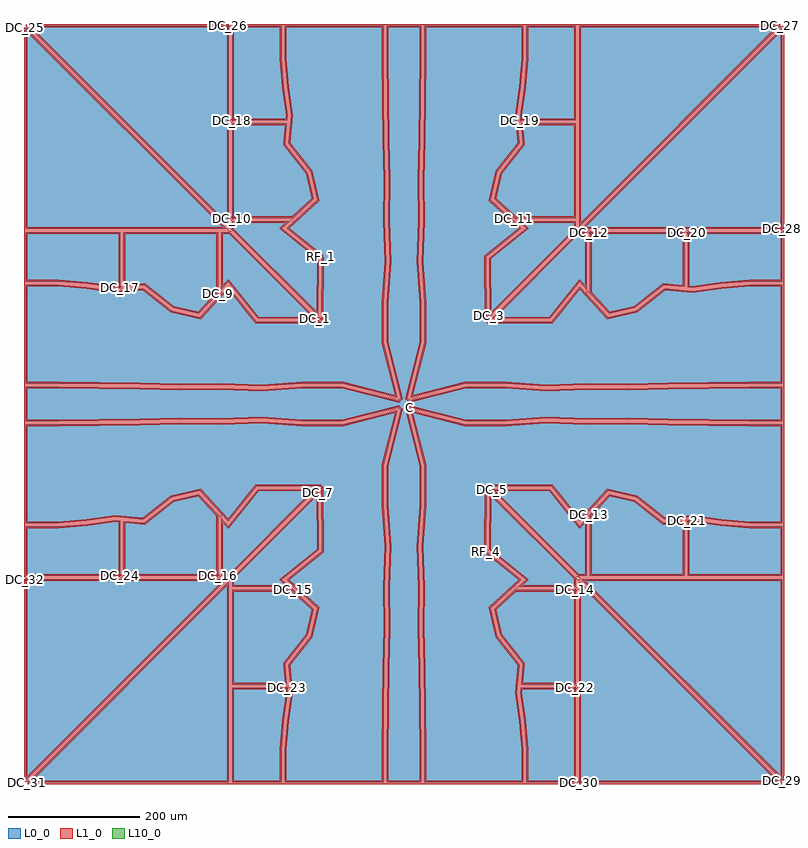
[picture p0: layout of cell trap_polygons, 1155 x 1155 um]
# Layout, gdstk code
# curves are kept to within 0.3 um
import gdstk
lib = gdstk.Library(unit=1e-6, precision=1e-09)
def P(c, l, *ps):  # polygons
    for p in ps: c.add(gdstk.Polygon(p, *l))
L0_0 = (0, 0)
L1_0 = (1, 0)
L10_0 = (10, 0)

trap_polygons = lib.new_cell('trap_polygons')
P(trap_polygons, L0_0, [(-575,-266.125),(-269.661,-266.125),(-575,-571.464),(-575,-266.125)],
  [(-571.464,-575),(-266.125,-269.661),(-266.125,-575),(-571.464,-575)],
  [(266.125,-575),(266.125,-269.661),(571.464,-575),(266.125,-575)],
  [(575,-571.464),(269.661,-266.125),(575,-266.125),(575,-571.464)],
  [(575,266.125),(269.661,266.125),(575,571.464),(575,266.125)],
  [(571.464,575),(266.125,269.661),(266.125,575),(571.464,575)],
  [(-266.125,575),(-266.125,269.661),(-571.464,575),(-266.125,575)],
  [(-575,571.464),(-269.661,266.125),(-575,266.125),(-575,571.464)],
  [(-431.321,-261.125),(-438.926,-261.125),(-481.19,-261.125),(-524.501,-261.125),(-575,-261.125),(-575,-186.125),(-524.501,-186.125),(-481.19,-182.401),(-438.926,-176.757),(-431.321,-177.452),(-431.321,-261.125)],
  [(-177.452,-431.321),(-176.757,-438.926),(-182.401,-481.19),(-186.125,-524.501),(-186.125,-575),(-261.125,-575),(-261.125,-524.501),(-261.125,-481.19),(-261.125,-438.926),(-261.125,-431.321),(-177.452,-431.321)],
  [(261.125,-431.321),(261.125,-438.926),(261.125,-481.19),(261.125,-524.501),(261.125,-575),(186.125,-575),(186.125,-524.501),(182.401,-481.19),(176.757,-438.926),(177.452,-431.321),(261.125,-431.321)],
  [(431.321,-177.452),(438.926,-176.757),(481.19,-182.401),(524.501,-186.125),(575,-186.125),(575,-261.125),(524.501,-261.125),(481.19,-261.125),(438.926,-261.125),(431.321,-261.125),(431.321,-177.452)],
  [(431.321,261.125),(438.926,261.125),(481.19,261.125),(524.501,261.125),(575,261.125),(575,186.125),(524.501,186.125),(481.19,182.401),(438.926,176.757),(431.321,177.452),(431.321,261.125)],
  [(177.452,431.321),(176.757,438.926),(182.401,481.19),(186.125,524.501),(186.125,575),(261.125,575),(261.125,524.501),(261.125,481.19),(261.125,438.926),(261.125,431.321),(177.452,431.321)],
  [(-261.125,431.321),(-261.125,438.926),(-261.125,481.19),(-261.125,524.501),(-261.125,575),(-186.125,575),(-186.125,524.501),(-182.401,481.19),(-176.757,438.926),(-177.452,431.321),(-261.125,431.321)],
  [(-431.321,177.452),(-438.926,176.757),(-481.19,182.401),(-524.501,186.125),(-575,186.125),(-575,261.125),(-524.501,261.125),(-481.19,261.125),(-438.926,261.125),(-431.321,261.125),(-431.321,177.452)],
  [(-282.643,-261.125),(-311.781,-261.125),(-350.84,-261.125),(-394.504,-261.125),(-426.321,-261.125),(-426.321,-177.909),(-394.504,-180.815),(-350.84,-146.071),(-311.781,-137.162),(-282.643,-168.581),(-282.643,-261.125)],
  [(-168.581,-282.643),(-137.162,-311.781),(-146.071,-350.84),(-180.815,-394.504),(-177.909,-426.321),(-261.125,-426.321),(-261.125,-394.504),(-261.125,-350.84),(-261.125,-311.781),(-261.125,-282.643),(-168.581,-282.643)],
  [(261.125,-282.643),(261.125,-311.781),(261.125,-350.84),(261.125,-394.504),(261.125,-426.321),(177.909,-426.321),(180.815,-394.504),(146.071,-350.84),(137.162,-311.781),(168.581,-282.643),(261.125,-282.643)],
  [(282.643,-168.581),(311.781,-137.162),(350.84,-146.071),(394.504,-180.815),(426.321,-177.909),(426.321,-261.125),(394.504,-261.125),(350.84,-261.125),(311.781,-261.125),(282.643,-261.125),(282.643,-168.581)],
  [(282.643,261.125),(311.781,261.125),(350.84,261.125),(394.504,261.125),(426.321,261.125),(426.321,177.909),(394.504,180.815),(350.84,146.071),(311.781,137.162),(282.643,168.581),(282.643,261.125)],
  [(168.581,282.643),(137.162,311.781),(146.071,350.84),(180.815,394.504),(177.909,426.321),(261.125,426.321),(261.125,394.504),(261.125,350.84),(261.125,311.781),(261.125,282.643),(168.581,282.643)],
  [(-261.125,282.643),(-261.125,311.781),(-261.125,350.84),(-261.125,394.504),(-261.125,426.321),(-177.909,426.321),(-180.815,394.504),(-146.071,350.84),(-137.162,311.781),(-168.581,282.643),(-261.125,282.643)],
  [(-282.643,168.581),(-311.781,137.162),(-350.84,146.071),(-394.504,180.815),(-426.321,177.909),(-426.321,261.125),(-394.504,261.125),(-350.84,261.125),(-311.781,261.125),(-282.643,261.125),(-282.643,168.581)],
  [(-264.661,-261.125),(-266.827,-261.125),(-277.643,-261.125),(-277.643,-173.972),(-266.827,-185.634),(-221.734,-129.646),(-133.964,-130.428),(-264.661,-261.125)],
  [(-130.428,-133.964),(-129.646,-221.734),(-185.634,-266.827),(-173.972,-277.643),(-261.125,-277.643),(-261.125,-266.827),(-261.125,-264.661),(-130.428,-133.964)],
  [(261.125,-264.661),(261.125,-266.827),(261.125,-277.643),(173.972,-277.643),(185.634,-266.827),(129.646,-221.734),(130.428,-133.964),(261.125,-264.661)],
  [(133.964,-130.428),(221.734,-129.646),(266.827,-185.634),(277.643,-173.972),(277.643,-261.125),(266.827,-261.125),(264.661,-261.125),(133.964,-130.428)],
  [(264.661,261.125),(266.827,261.125),(277.643,261.125),(277.643,173.972),(266.827,185.634),(221.734,129.646),(133.964,130.428),(264.661,261.125)],
  [(130.428,133.964),(129.646,221.734),(185.634,266.827),(173.972,277.643),(261.125,277.643),(261.125,266.827),(261.125,264.661),(130.428,133.964)],
  [(-261.125,264.661),(-261.125,266.827),(-261.125,277.643),(-173.972,277.643),(-185.634,266.827),(-129.646,221.734),(-130.428,133.964),(-261.125,264.661)],
  [(-133.964,130.428),(-221.734,129.646),(-266.827,185.634),(-277.643,173.972),(-277.643,261.125),(-266.827,261.125),(-264.661,261.125),(-133.964,130.428)],
  [(8.315,-5.556),(6.344,-7.73),(4.563,-8.89),(26.091,-93.487),(26.125,-154.417),(21.725,-216.238),(23.897,-278.128),(23.354,-339.827),(25.43,-463.123),(26.125,-525),(26.125,-575),(-26.125,-575),(-26.125,-525),(-25.43,-463.123),(-23.354,-339.827),(-23.897,-278.128),(-21.725,-216.238),(-26.125,-154.417),(-26.091,-93.487),(-4.563,-8.89),(-7.071,-7.071),(-8.89,-4.563),(-93.487,-26.091),(-154.417,-26.125),(-216.238,-21.725),(-278.128,-23.897),(-339.827,-23.354),(-463.123,-25.43),(-525,-26.125),(-575,-26.125),(-575,26.125),(-525,26.125),(-463.123,25.43),(-339.827,23.354),(-278.128,23.897),(-216.238,21.725),(-154.417,26.125),(-93.487,26.091),(-8.89,4.563),(-7.071,7.071),(-4.563,8.89),(-26.091,93.487),(-26.125,154.417),(-21.725,216.238),(-23.897,278.128),(-23.354,339.827),(-25.43,463.123),(-26.125,525),(-26.125,575),(26.125,575),(26.125,525),(25.43,463.123),(23.354,339.827),(23.897,278.128),(21.725,216.238),(26.125,154.417),(26.091,93.487),(4.563,8.89),(7.071,7.071),(8.89,4.563),(93.487,26.091),(154.417,26.125),(216.238,21.725),(278.128,23.897),(339.827,23.354),(463.123,25.43),(525,26.125),(575,26.125),(575,-26.125),(525,-26.125),(463.123,-25.43),(339.827,-23.354),(278.128,-23.897),(216.238,-21.725),(154.417,-26.125),(93.487,-26.091),(8.89,-4.563)],
  [(124.625,-224.109),(177.993,-267.094),(131.645,-310.078),(141.449,-353.062),(175.653,-396.047),(171.727,-439.031),(177.467,-482.016),(181.125,-525),(181.125,-575),(31.125,-575),(31.125,-525),(30.432,-463.266),(28.355,-339.797),(28.898,-278.062),(26.731,-216.328),(31.125,-154.594),(31.091,-92.859),(10.007,-10.007),(92.859,-31.091),(154.594,-31.125),(216.328,-26.731),(278.062,-28.898),(339.797,-28.355),(463.266,-30.432),(525,-31.125),(575,-31.125),(575,-181.125),(525,-181.125),(482.016,-177.467),(439.031,-171.727),(396.047,-175.653),(353.062,-141.449),(310.078,-131.645),(267.094,-177.993),(224.109,-124.625),(125.504,-125.504)],
  [(125.504,125.504),(224.109,124.625),(267.094,177.993),(310.078,131.645),(353.062,141.449),(396.047,175.653),(439.031,171.727),(482.016,177.467),(525,181.125),(575,181.125),(575,31.125),(525,31.125),(463.266,30.432),(339.797,28.355),(278.062,28.898),(216.328,26.731),(154.594,31.125),(92.859,31.091),(10.007,10.007),(31.091,92.859),(31.125,154.594),(26.731,216.328),(28.898,278.062),(28.355,339.797),(30.432,463.266),(31.125,525),(31.125,575),(181.125,575),(181.125,525),(177.467,482.016),(171.727,439.031),(175.653,396.047),(141.449,353.062),(131.645,310.078),(177.993,267.094),(124.625,224.109)],
  [(-125.504,-125.504),(-224.109,-124.625),(-267.094,-177.993),(-310.078,-131.645),(-353.062,-141.449),(-396.047,-175.653),(-439.031,-171.727),(-482.016,-177.467),(-525,-181.125),(-575,-181.125),(-575,-31.125),(-525,-31.125),(-463.266,-30.432),(-339.797,-28.355),(-278.062,-28.898),(-216.328,-26.731),(-154.594,-31.125),(-92.859,-31.091),(-10.007,-10.007),(-31.091,-92.859),(-31.125,-154.594),(-26.731,-216.328),(-28.898,-278.062),(-28.355,-339.797),(-30.432,-463.266),(-31.125,-525),(-31.125,-575),(-181.125,-575),(-181.125,-525),(-177.467,-482.016),(-171.727,-439.031),(-175.653,-396.047),(-141.449,-353.062),(-131.645,-310.078),(-177.993,-267.094),(-124.625,-224.109)],
  [(-124.625,224.109),(-177.993,267.094),(-131.645,310.078),(-141.449,353.062),(-175.653,396.047),(-171.727,439.031),(-177.467,482.016),(-181.125,525),(-181.125,575),(-31.125,575),(-31.125,525),(-30.432,463.266),(-28.355,339.797),(-28.898,278.062),(-26.731,216.328),(-31.125,154.594),(-31.091,92.859),(-10.007,10.007),(-92.859,31.091),(-154.594,31.125),(-216.328,26.731),(-278.062,28.898),(-339.797,28.355),(-463.266,30.432),(-525,31.125),(-575,31.125),(-575,181.125),(-525,181.125),(-482.016,177.467),(-439.031,171.727),(-396.047,175.653),(-353.062,141.449),(-310.078,131.645),(-267.094,177.993),(-224.109,124.625),(-125.504,125.504)])
P(trap_polygons, L1_0, [(-575,-263.625),(-575,-268.625),(-275.696,-268.625),(-572.5,-565.429),(-572.5,-266.125),(-577.5,-266.125),(-577.5,-573.964),(-575,-575),(-266.125,-266.125),(-267.161,-263.625)],
  [(-573.232,-573.232),(-569.697,-576.768),(-268.625,-275.696),(-268.625,-572.5),(-571.464,-572.5),(-571.464,-577.5),(-263.625,-577.5),(-263.625,-267.161),(-266.125,-266.125)],
  [(263.625,-575),(268.625,-575),(268.625,-275.696),(565.429,-572.5),(266.125,-572.5),(266.125,-577.5),(573.964,-577.5),(575,-575),(266.125,-266.125),(263.625,-267.161)],
  [(573.232,-573.232),(576.768,-569.697),(275.696,-268.625),(572.5,-268.625),(572.5,-571.464),(577.5,-571.464),(577.5,-263.625),(267.161,-263.625),(266.125,-266.125)],
  [(575,263.625),(575,268.625),(275.696,268.625),(572.5,565.429),(572.5,266.125),(577.5,266.125),(577.5,573.964),(575,575),(266.125,266.125),(267.161,263.625)],
  [(573.232,573.232),(569.697,576.768),(268.625,275.696),(268.625,572.5),(571.464,572.5),(571.464,577.5),(263.625,577.5),(263.625,267.161),(266.125,266.125)],
  [(-263.625,575),(-268.625,575),(-268.625,275.696),(-565.429,572.5),(-266.125,572.5),(-266.125,577.5),(-573.964,577.5),(-575,575),(-266.125,266.125),(-263.625,267.161)],
  [(-573.232,573.232),(-576.768,569.697),(-275.696,268.625),(-572.5,268.625),(-572.5,571.464),(-577.5,571.464),(-577.5,263.625),(-267.161,263.625),(-266.125,266.125)],
  [(-431.321,-263.625),(-431.321,-258.625),(-572.5,-258.625),(-572.5,-188.625),(-524.394,-188.625),(-480.917,-184.887),(-438.874,-179.272),(-433.821,-179.734),(-433.821,-261.125),(-428.821,-261.125),(-428.821,-175.17),(-438.979,-174.242),(-481.463,-179.915),(-524.609,-183.625),(-577.5,-183.625),(-577.5,-263.625)],
  [(-174.962,-431.094),(-179.942,-431.549),(-179.272,-438.874),(-184.887,-480.917),(-188.625,-524.394),(-188.625,-572.5),(-258.625,-572.5),(-258.625,-433.821),(-177.452,-433.821),(-177.452,-428.821),(-263.625,-428.821),(-263.625,-577.5),(-183.625,-577.5),(-183.625,-524.609),(-179.915,-481.463),(-174.242,-438.979)],
  [(263.625,-431.321),(258.625,-431.321),(258.625,-572.5),(188.625,-572.5),(188.625,-524.394),(184.887,-480.917),(179.272,-438.874),(179.734,-433.821),(261.125,-433.821),(261.125,-428.821),(175.17,-428.821),(174.242,-438.979),(179.915,-481.463),(183.625,-524.609),(183.625,-577.5),(263.625,-577.5)],
  [(431.094,-174.962),(431.549,-179.942),(438.874,-179.272),(480.917,-184.887),(524.394,-188.625),(572.5,-188.625),(572.5,-258.625),(433.821,-258.625),(433.821,-177.452),(428.821,-177.452),(428.821,-263.625),(577.5,-263.625),(577.5,-183.625),(524.609,-183.625),(481.463,-179.915),(438.979,-174.242)],
  [(431.321,263.625),(431.321,258.625),(572.5,258.625),(572.5,188.625),(524.394,188.625),(480.917,184.887),(438.874,179.272),(433.821,179.734),(433.821,261.125),(428.821,261.125),(428.821,175.17),(438.979,174.242),(481.463,179.915),(524.609,183.625),(577.5,183.625),(577.5,263.625)],
  [(174.962,431.094),(179.942,431.549),(179.272,438.874),(184.887,480.917),(188.625,524.394),(188.625,572.5),(258.625,572.5),(258.625,433.821),(177.452,433.821),(177.452,428.821),(263.625,428.821),(263.625,577.5),(183.625,577.5),(183.625,524.609),(179.915,481.463),(174.242,438.979)],
  [(-263.625,431.321),(-258.625,431.321),(-258.625,572.5),(-188.625,572.5),(-188.625,524.394),(-184.887,480.917),(-179.272,438.874),(-179.734,433.821),(-261.125,433.821),(-261.125,428.821),(-175.17,428.821),(-174.242,438.979),(-179.915,481.463),(-183.625,524.609),(-183.625,577.5),(-263.625,577.5)],
  [(-431.094,174.962),(-431.549,179.942),(-438.874,179.272),(-480.917,184.887),(-524.394,188.625),(-572.5,188.625),(-572.5,258.625),(-433.821,258.625),(-433.821,177.452),(-428.821,177.452),(-428.821,263.625),(-577.5,263.625),(-577.5,183.625),(-524.609,183.625),(-481.463,179.915),(-438.979,174.242)],
  [(-282.643,-263.625),(-282.643,-258.625),(-423.821,-258.625),(-423.821,-180.647),(-393.732,-183.396),(-349.729,-148.381),(-312.632,-139.92),(-285.143,-169.562),(-285.143,-261.125),(-280.143,-261.125),(-280.143,-167.6),(-310.93,-134.403),(-351.951,-143.76),(-395.275,-178.234),(-428.821,-175.409),(-428.821,-263.625)],
  [(-166.881,-280.81),(-170.281,-284.476),(-139.92,-312.632),(-148.381,-349.729),(-183.396,-393.732),(-180.647,-423.821),(-258.625,-423.821),(-258.625,-285.143),(-168.581,-285.143),(-168.581,-280.143),(-263.625,-280.143),(-263.625,-428.821),(-175.192,-428.583),(-178.234,-395.275),(-143.76,-351.951),(-134.403,-310.93)],
  [(263.625,-282.643),(258.625,-282.643),(258.625,-423.821),(180.647,-423.821),(183.396,-393.732),(148.381,-349.729),(139.92,-312.632),(169.562,-285.143),(261.125,-285.143),(261.125,-280.143),(167.6,-280.143),(134.403,-310.93),(143.76,-351.951),(178.234,-395.275),(175.409,-428.821),(263.625,-428.821)],
  [(280.81,-166.881),(284.476,-170.281),(312.632,-139.92),(349.729,-148.381),(393.732,-183.396),(423.821,-180.647),(423.821,-258.625),(285.143,-258.625),(285.143,-168.581),(280.143,-168.581),(280.143,-263.625),(428.821,-263.625),(428.583,-175.192),(395.275,-178.234),(351.951,-143.76),(310.93,-134.403)],
  [(282.643,263.625),(282.643,258.625),(423.821,258.625),(423.821,180.647),(393.732,183.396),(349.729,148.381),(312.632,139.92),(285.143,169.562),(285.143,261.125),(280.143,261.125),(280.143,167.6),(310.93,134.403),(351.951,143.76),(395.275,178.234),(428.821,175.409),(428.821,263.625)],
  [(166.881,280.81),(170.281,284.476),(139.92,312.632),(148.381,349.729),(183.396,393.732),(180.647,423.821),(258.625,423.821),(258.625,285.143),(168.581,285.143),(168.581,280.143),(263.625,280.143),(263.625,428.821),(175.192,428.583),(178.234,395.275),(143.76,351.951),(134.403,310.93)],
  [(-263.625,282.643),(-258.625,282.643),(-258.625,423.821),(-180.647,423.821),(-183.396,393.732),(-148.381,349.729),(-139.92,312.632),(-169.562,285.143),(-261.125,285.143),(-261.125,280.143),(-167.6,280.143),(-134.403,310.93),(-143.76,351.951),(-178.234,395.275),(-175.409,428.821),(-263.625,428.821)],
  [(-280.81,166.881),(-284.476,170.281),(-312.632,139.92),(-349.729,148.381),(-393.732,183.396),(-423.821,180.647),(-423.821,258.625),(-285.143,258.625),(-285.143,168.581),(-280.143,168.581),(-280.143,263.625),(-428.821,263.625),(-428.583,175.192),(-395.275,178.234),(-351.951,143.76),(-310.93,134.403)],
  [(-264.661,-263.625),(-264.661,-258.625),(-275.143,-258.625),(-275.143,-180.344),(-266.96,-189.167),(-266.448,-189.149),(-220.546,-132.157),(-139.946,-132.875),(-266.428,-259.357),(-262.893,-262.893),(-130.428,-130.428),(-131.442,-127.951),(-222.921,-127.136),(-266.961,-181.814),(-277.51,-170.439),(-280.143,-171.472),(-280.143,-263.625)],
  [(-127.929,-133.942),(-132.928,-133.986),(-132.157,-220.546),(-189.149,-266.448),(-189.167,-266.96),(-180.344,-275.143),(-258.625,-275.143),(-258.625,-265.696),(-128.661,-135.732),(-132.196,-132.196),(-263.625,-263.625),(-263.625,-280.143),(-171.472,-280.143),(-170.439,-277.51),(-181.814,-266.961),(-127.136,-222.921)],
  [(263.625,-264.661),(258.625,-264.661),(258.625,-275.143),(180.344,-275.143),(189.167,-266.96),(189.149,-266.448),(132.157,-220.546),(132.875,-139.946),(259.357,-266.428),(262.893,-262.893),(130.428,-130.428),(127.951,-131.442),(127.136,-222.921),(181.814,-266.961),(170.439,-277.51),(171.472,-280.143),(263.625,-280.143)],
  [(133.942,-127.929),(133.986,-132.928),(220.546,-132.157),(266.448,-189.149),(266.96,-189.167),(275.143,-180.344),(275.143,-258.625),(265.696,-258.625),(135.732,-128.661),(132.196,-132.196),(263.625,-263.625),(280.143,-263.625),(280.143,-171.472),(277.51,-170.439),(266.961,-181.814),(222.921,-127.136)],
  [(264.661,263.625),(264.661,258.625),(275.143,258.625),(275.143,180.344),(266.96,189.167),(266.448,189.149),(220.546,132.157),(139.946,132.875),(266.428,259.357),(262.893,262.893),(130.428,130.428),(131.442,127.951),(222.921,127.136),(266.961,181.814),(277.51,170.439),(280.143,171.472),(280.143,263.625)],
  [(127.929,133.942),(132.928,133.986),(132.157,220.546),(189.149,266.448),(189.167,266.96),(180.344,275.143),(258.625,275.143),(258.625,265.696),(128.661,135.732),(132.196,132.196),(263.625,263.625),(263.625,280.143),(171.472,280.143),(170.439,277.51),(181.814,266.961),(127.136,222.921)],
  [(-263.625,264.661),(-258.625,264.661),(-258.625,275.143),(-180.344,275.143),(-189.167,266.96),(-189.149,266.448),(-132.157,220.546),(-132.875,139.946),(-259.357,266.428),(-262.893,262.893),(-130.428,130.428),(-127.951,131.442),(-127.136,222.921),(-181.814,266.961),(-170.439,277.51),(-171.472,280.143),(-263.625,280.143)],
  [(-133.942,127.929),(-133.986,132.928),(-220.546,132.157),(-266.448,189.149),(-266.96,189.167),(-275.143,180.344),(-275.143,258.625),(-265.696,258.625),(-135.732,128.661),(-132.196,132.196),(-263.625,263.625),(-280.143,263.625),(-280.143,171.472),(-277.51,170.439),(-266.961,181.814),(-222.921,127.136)],
  [(28.625,-524.986),(27.141,-401.573),(25.855,-339.812),(26.397,-278.095),(24.228,-216.283),(28.625,-154.506),(28.591,-93.173),(7.494,-10.27),(5.894,-11.027),(7.932,-9.665),(10.323,-7.045),(8.317,-5.557),(10.459,-6.841),(11.027,-5.894),(10.27,-7.494),(93.173,-28.591),(154.506,-28.625),(216.283,-24.228),(278.095,-26.397),(339.812,-25.855),(463.093,-27.93),(524.986,-28.625),(577.5,-28.625),(577.5,-1.633),(572.5,-1.633),(572.5,-23.625),(525.014,-23.625),(463.154,-22.93),(339.842,-20.854),(278.161,-21.397),(216.193,-19.222),(154.329,-23.625),(93.801,-23.591),(7.511,-1.633),(5.301,-5.301),(1.633,-7.511),(23.591,-93.801),(23.625,-154.329),(19.222,-216.193),(21.397,-278.161),(20.854,-339.842),(22.93,-463.154),(23.625,-525.014),(23.625,-572.5),(-23.625,-572.5),(-23.625,-525.014),(-22.93,-463.154),(-20.854,-339.842),(-21.397,-278.161),(-19.222,-216.193),(-23.625,-154.329),(-23.591,-93.801),(-1.633,-7.511),(-5.301,-5.301),(-7.511,-1.633),(-93.801,-23.591),(-154.329,-23.625),(-216.193,-19.222),(-278.161,-21.397),(-339.842,-20.854),(-463.154,-22.93),(-525.014,-23.625),(-572.5,-23.625),(-572.5,-1.633),(-577.5,-1.633),(-577.5,-28.625),(-524.986,-28.625),(-463.093,-27.93),(-339.812,-25.855),(-278.095,-26.397),(-216.283,-24.228),(-154.506,-28.625),(-93.173,-28.591),(-10.27,-7.494),(-11.027,-5.894),(-8.841,-8.841),(-5.894,-11.027),(-7.494,-10.27),(-28.591,-93.173),(-28.625,-154.506),(-24.228,-216.283),(-26.397,-278.095),(-25.855,-339.812),(-27.93,-463.093),(-28.625,-524.986),(-28.625,-577.5),(28.625,-577.5)],
  [(577.5,28.625),(524.986,28.625),(463.093,27.93),(339.812,25.855),(278.095,26.397),(216.283,24.228),(154.506,28.625),(93.173,28.591),(10.27,7.494),(11.027,5.894),(8.841,8.841),(5.894,11.027),(7.494,10.27),(28.591,93.173),(28.625,154.506),(24.228,216.283),(26.397,278.095),(25.855,339.812),(27.93,463.093),(28.625,524.986),(28.625,577.5),(-28.625,577.5),(-28.625,524.986),(-27.93,463.093),(-25.855,339.812),(-26.397,278.095),(-24.228,216.283),(-28.625,154.506),(-28.591,93.173),(-7.494,10.27),(-5.894,11.027),(-8.841,8.841),(-11.027,5.894),(-10.27,7.494),(-93.173,28.591),(-154.506,28.625),(-216.283,24.228),(-278.095,26.397),(-339.812,25.855),(-463.093,27.93),(-524.986,28.625),(-577.5,28.625),(-577.5,-1.633),(-572.5,-1.633),(-572.5,23.625),(-525.014,23.625),(-463.154,22.93),(-339.842,20.854),(-278.161,21.397),(-216.193,19.222),(-154.329,23.625),(-93.801,23.591),(-7.511,1.633),(-5.301,5.301),(-1.633,7.511),(-23.591,93.801),(-23.625,154.329),(-19.222,216.193),(-21.397,278.161),(-20.854,339.842),(-22.93,463.154),(-23.625,525.014),(-23.625,572.5),(23.625,572.5),(23.625,525.014),(22.93,463.154),(20.854,339.842),(21.397,278.161),(19.222,216.193),(23.625,154.329),(23.591,93.801),(1.633,7.511),(5.301,5.301),(7.511,1.633),(93.801,23.591),(154.329,23.625),(216.193,19.222),(278.161,21.397),(339.842,20.854),(463.154,22.93),(525.014,23.625),(572.5,23.625),(572.5,-1.633),(577.5,-1.633)],
  [(126.193,-222.162),(123.057,-226.056),(174.173,-267.227),(128.887,-309.227),(139.138,-354.174),(173.072,-396.819),(169.212,-439.084),(174.981,-482.287),(178.625,-525.106),(178.625,-572.5),(33.625,-572.5),(33.625,-524.986),(32.932,-463.236),(30.855,-339.782),(31.398,-278.03),(29.234,-216.373),(33.625,-154.682),(33.591,-92.546),(13.467,-13.467),(92.546,-33.591),(154.682,-33.625),(216.373,-29.234),(278.03,-31.398),(339.782,-30.855),(463.236,-32.932),(524.986,-33.625),(572.5,-33.625),(572.5,-178.625),(525.106,-178.625),(482.287,-174.981),(439.084,-169.212),(396.819,-173.072),(354.174,-139.138),(309.227,-128.887),(267.227,-174.173),(225.297,-122.114),(123.026,-123.026),(122.125,-224.087),(127.125,-224.132),(127.982,-127.982),(222.921,-127.136),(266.715,-181.509),(267.227,-181.526),(310.93,-134.403),(351.951,-143.76),(395.275,-178.234),(438.979,-174.242),(481.744,-179.953),(524.894,-183.625),(577.5,-183.625),(577.5,-28.625),(525.014,-28.625),(463.296,-27.933),(339.812,-25.855),(278.095,-26.397),(216.283,-24.228),(154.506,-28.625),(93.173,-28.591),(8.201,-6.968),(6.968,-8.201),(28.591,-93.173),(28.625,-154.506),(24.228,-216.283),(26.397,-278.095),(25.855,-339.812),(27.933,-463.296),(28.625,-525.014),(28.625,-577.5),(183.625,-577.5),(183.625,-524.894),(179.953,-481.744),(174.242,-438.979),(178.234,-395.275),(143.76,-351.951),(134.403,-310.93),(181.526,-267.227),(181.509,-266.715)],
  [(125.526,128.004),(125.481,123.004),(225.297,122.114),(267.227,174.173),(309.227,128.887),(354.174,139.138),(396.819,173.072),(439.084,169.212),(482.287,174.981),(525.106,178.625),(572.5,178.625),(572.5,33.625),(524.986,33.625),(463.236,32.932),(339.782,30.855),(278.03,31.398),(216.373,29.234),(154.682,33.625),(92.546,33.591),(13.467,13.467),(33.591,92.546),(33.625,154.682),(29.234,216.373),(31.398,278.03),(30.855,339.782),(32.932,463.236),(33.625,524.986),(33.625,572.5),(178.625,572.5),(178.625,525.106),(174.981,482.287),(169.212,439.084),(173.072,396.819),(139.138,354.174),(128.887,309.227),(174.173,267.227),(122.114,225.297),(123.004,125.481),(128.004,125.526),(127.136,222.921),(181.509,266.715),(181.526,267.227),(134.403,310.93),(143.76,351.951),(178.234,395.275),(174.242,438.979),(179.953,481.744),(183.625,524.894),(183.625,577.5),(28.625,577.5),(28.625,525.014),(27.933,463.296),(25.855,339.812),(26.397,278.095),(24.228,216.283),(28.625,154.506),(28.591,93.173),(6.968,8.201),(8.201,6.968),(93.173,28.591),(154.506,28.625),(216.283,24.228),(278.095,26.397),(339.812,25.855),(463.296,27.933),(525.014,28.625),(577.5,28.625),(577.5,183.625),(524.894,183.625),(481.744,179.953),(438.979,174.242),(395.275,178.234),(351.951,143.76),(310.93,134.403),(267.227,181.526),(266.715,181.509),(222.921,127.136)],
  [(-125.526,-128.004),(-125.481,-123.004),(-225.297,-122.114),(-267.227,-174.173),(-309.227,-128.887),(-354.174,-139.138),(-396.819,-173.072),(-439.084,-169.212),(-482.287,-174.981),(-525.106,-178.625),(-572.5,-178.625),(-572.5,-33.625),(-524.986,-33.625),(-463.236,-32.932),(-339.782,-30.855),(-278.03,-31.398),(-216.373,-29.234),(-154.682,-33.625),(-92.546,-33.591),(-13.467,-13.467),(-33.591,-92.546),(-33.625,-154.682),(-29.234,-216.373),(-31.398,-278.03),(-30.855,-339.782),(-32.932,-463.236),(-33.625,-524.986),(-33.625,-572.5),(-178.625,-572.5),(-178.625,-525.106),(-174.981,-482.287),(-169.212,-439.084),(-173.072,-396.819),(-139.138,-354.174),(-128.887,-309.227),(-174.173,-267.227),(-122.114,-225.297),(-123.004,-125.481),(-128.004,-125.526),(-127.136,-222.921),(-181.509,-266.715),(-181.526,-267.227),(-134.403,-310.93),(-143.76,-351.951),(-178.234,-395.275),(-174.242,-438.979),(-179.953,-481.744),(-183.625,-524.894),(-183.625,-577.5),(-28.625,-577.5),(-28.625,-525.014),(-27.933,-463.296),(-25.855,-339.812),(-26.397,-278.095),(-24.228,-216.283),(-28.625,-154.506),(-28.591,-93.173),(-6.968,-8.201),(-8.201,-6.968),(-93.173,-28.591),(-154.506,-28.625),(-216.283,-24.228),(-278.095,-26.397),(-339.812,-25.855),(-463.296,-27.933),(-525.014,-28.625),(-577.5,-28.625),(-577.5,-183.625),(-524.894,-183.625),(-481.744,-179.953),(-438.979,-174.242),(-395.275,-178.234),(-351.951,-143.76),(-310.93,-134.403),(-267.227,-181.526),(-266.715,-181.509),(-222.921,-127.136)],
  [(-126.193,222.162),(-123.057,226.056),(-174.173,267.227),(-128.887,309.227),(-139.138,354.174),(-173.072,396.819),(-169.212,439.084),(-174.981,482.287),(-178.625,525.106),(-178.625,572.5),(-33.625,572.5),(-33.625,524.986),(-32.932,463.236),(-30.855,339.782),(-31.398,278.03),(-29.234,216.373),(-33.625,154.682),(-33.591,92.546),(-13.467,13.467),(-92.546,33.591),(-154.682,33.625),(-216.373,29.234),(-278.03,31.398),(-339.782,30.855),(-463.236,32.932),(-524.986,33.625),(-572.5,33.625),(-572.5,178.625),(-525.106,178.625),(-482.287,174.981),(-439.084,169.212),(-396.819,173.072),(-354.174,139.138),(-309.227,128.887),(-267.227,174.173),(-225.297,122.114),(-123.026,123.026),(-122.125,224.087),(-127.125,224.132),(-127.982,127.982),(-222.921,127.136),(-266.715,181.509),(-267.227,181.526),(-310.93,134.403),(-351.951,143.76),(-395.275,178.234),(-438.979,174.242),(-481.744,179.953),(-524.894,183.625),(-577.5,183.625),(-577.5,28.625),(-525.014,28.625),(-463.296,27.933),(-339.812,25.855),(-278.095,26.397),(-216.283,24.228),(-154.506,28.625),(-93.173,28.591),(-8.201,6.968),(-6.968,8.201),(-28.591,93.173),(-28.625,154.506),(-24.228,216.283),(-26.397,278.095),(-25.855,339.812),(-27.933,463.296),(-28.625,525.014),(-28.625,577.5),(-183.625,577.5),(-183.625,524.894),(-179.953,481.744),(-174.242,438.979),(-178.234,395.275),(-143.76,351.951),(-134.403,310.93),(-181.526,267.227),(-181.509,266.715)])
P(trap_polygons, L10_0, [(0,0),(0,0),(0,0),(0,0)])
trap_polygons.add(gdstk.Label('DC_32', (-575,-266.125), layer=2, texttype=0))
trap_polygons.add(gdstk.Label('DC_31', (-571.464,-575), layer=2, texttype=0))
trap_polygons.add(gdstk.Label('DC_30', (266.125,-575), layer=2, texttype=0))
trap_polygons.add(gdstk.Label('DC_29', (575,-571.464), layer=2, texttype=0))
trap_polygons.add(gdstk.Label('DC_28', (575,266.125), layer=2, texttype=0))
trap_polygons.add(gdstk.Label('DC_27', (571.464,575), layer=2, texttype=0))
trap_polygons.add(gdstk.Label('DC_26', (-266.125,575), layer=2, texttype=0))
trap_polygons.add(gdstk.Label('DC_25', (-575,571.464), layer=2, texttype=0))
trap_polygons.add(gdstk.Label('DC_24', (-431.321,-261.125), layer=2, texttype=0))
trap_polygons.add(gdstk.Label('DC_23', (-177.452,-431.321), layer=2, texttype=0))
trap_polygons.add(gdstk.Label('DC_22', (261.125,-431.321), layer=2, texttype=0))
trap_polygons.add(gdstk.Label('DC_21', (431.321,-177.452), layer=2, texttype=0))
trap_polygons.add(gdstk.Label('DC_20', (431.321,261.125), layer=2, texttype=0))
trap_polygons.add(gdstk.Label('DC_19', (177.452,431.321), layer=2, texttype=0))
trap_polygons.add(gdstk.Label('DC_18', (-261.125,431.321), layer=2, texttype=0))
trap_polygons.add(gdstk.Label('DC_17', (-431.321,177.452), layer=2, texttype=0))
trap_polygons.add(gdstk.Label('DC_16', (-282.643,-261.125), layer=2, texttype=0))
trap_polygons.add(gdstk.Label('DC_15', (-168.581,-282.643), layer=2, texttype=0))
trap_polygons.add(gdstk.Label('DC_14', (261.125,-282.643), layer=2, texttype=0))
trap_polygons.add(gdstk.Label('DC_13', (282.643,-168.581), layer=2, texttype=0))
trap_polygons.add(gdstk.Label('DC_12', (282.643,261.125), layer=2, texttype=0))
trap_polygons.add(gdstk.Label('DC_11', (168.581,282.643), layer=2, texttype=0))
trap_polygons.add(gdstk.Label('DC_10', (-261.125,282.643), layer=2, texttype=0))
trap_polygons.add(gdstk.Label('DC_9', (-282.643,168.581), layer=2, texttype=0))
trap_polygons.add(gdstk.Label('DC_8', (-264.661,-261.125), layer=2, texttype=0))
trap_polygons.add(gdstk.Label('DC_7', (-130.428,-133.964), layer=2, texttype=0))
trap_polygons.add(gdstk.Label('DC_6', (261.125,-264.661), layer=2, texttype=0))
trap_polygons.add(gdstk.Label('DC_5', (133.964,-130.428), layer=2, texttype=0))
trap_polygons.add(gdstk.Label('DC_4', (264.661,261.125), layer=2, texttype=0))
trap_polygons.add(gdstk.Label('DC_3', (130.428,133.964), layer=2, texttype=0))
trap_polygons.add(gdstk.Label('DC_2', (-261.125,264.661), layer=2, texttype=0))
trap_polygons.add(gdstk.Label('DC_1', (-133.964,130.428), layer=2, texttype=0))
trap_polygons.add(gdstk.Label('C', (8.315,-5.556), layer=2, texttype=0))
trap_polygons.add(gdstk.Label('RF_4', (124.625,-224.109), layer=2, texttype=0))
trap_polygons.add(gdstk.Label('RF_3', (125.504,125.504), layer=2, texttype=0))
trap_polygons.add(gdstk.Label('RF_2', (-125.504,-125.504), layer=2, texttype=0))
trap_polygons.add(gdstk.Label('RF_1', (-124.625,224.109), layer=2, texttype=0))

lib.write_gds('trap_polygons.gds')
